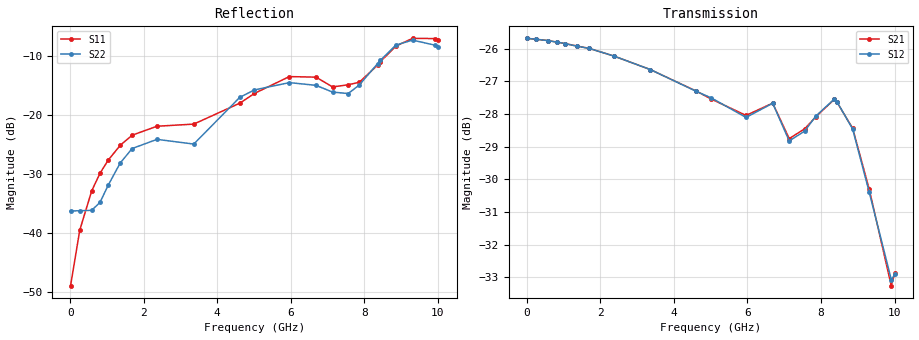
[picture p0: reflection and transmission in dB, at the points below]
! Device ID: PE43704
! Dir: z:\PE43704\PE43704_Char_1_20130516\PE43704\AMB\3p400V\24p75dB
! Serial: 14
! Insertion: A
! Impedance: 50 ohm
! Temp: Amb
! VDD: 3.400V
! Attenuation Step: 24.75dB
! IDD: 1.140146e-01mA
#  Hz  S  RI  R  50
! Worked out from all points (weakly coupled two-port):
!   401 points, 10 MHz to 10.01 GHz, reference 50 ohm
!   highest |S21| = -25.68 dB at 10 MHz (marker M1); lowest = -33.2 dB at 9.91 GHz (marker M2)
!   lowest |S11| = -48.9 dB at 10 MHz (marker M3), VSWR 1.01, Z = 50.4 + j0.0427 ohm
!   |S11| at or under -10 dB: start of sweep to 8.562 GHz
!   |S22| runs from -36.3 to -7.2 dB; largest |S21 - S12| = 0.0006
!   S11 on the Smith chart (normalised r, x): 10 MHz: 1.01, +0.00; 4.61 GHz: 0.79, +0.08; 8.435 GHz: 0.76, +0.46; 9.31 GHz: 0.51, +0.52; 10.01 GHz: 0.44, +0.31
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1e7  0.00358 0.000424  0.052 -9.25e-05  0.052 -6.29e-05  0.0155 0.000298
2.6e8  0.00114 0.0106  0.0517 -0.00359  0.0517 -0.00355  0.013 0.00852
5.85e8  -0.00966 0.0208  0.051 -0.00782  0.051 -0.00773  0.00244 0.0155
8.1e8  -0.0214 0.0242  0.0502 -0.0106  0.0502 -0.0107  -0.00851 0.0162
1.035e9  -0.0345 0.0236  0.0493 -0.0133  0.0493 -0.0133  -0.0217 0.0137
1.36e9  -0.053 0.0172  0.0476 -0.0172  0.0476 -0.0171  -0.0392 0.00454
1.685e9  -0.0676 0.00646  0.0457 -0.0208  0.0457 -0.0208  -0.0517 -0.0082
2.36e9  -0.0796 -0.0142  0.0406 -0.0272  0.0406 -0.0272  -0.0573 -0.0252
3.36e9  -0.0836 -0.0108  0.0315 -0.0343  0.0315 -0.0343  -0.057 -0.00322
4.61e9  -0.1165 0.0498  0.0201 -0.0382  0.02 -0.0382  -0.1279 0.0615
5.01e9  -0.1359 0.071  0.0172 -0.0383  0.0174 -0.0384  -0.1502 0.0663
5.96e9  -0.1866 0.1027  0.00975 -0.0384  0.0098 -0.0381  -0.1727 0.0778
6.685e9  -0.1873 0.0963  0.00556 -0.041  0.00539 -0.041  -0.1568 0.0873
7.135e9  -0.1548 0.0796  -0.000396 -0.0365  -0.000405 -0.0362  -0.1149 0.1076
7.56e9  -0.1297 0.127  -0.000491 -0.0378  -0.000403 -0.0375  -0.0731 0.1344
7.86e9  -0.094 0.1658  -0.00183 -0.0394  -0.00177 -0.0395  -0.0596 0.1704
8.36e9  -0.0595 0.2596  -0.0112 -0.0404  -0.011 -0.0405  -0.0662 0.2662
8.435e9  -0.0608 0.2788  -0.0127 -0.0395  -0.0123 -0.0397  -0.0732 0.2832
8.86e9  -0.1005 0.3729  -0.0189 -0.0328  -0.0187 -0.0328  -0.1202 0.3755
9.31e9  -0.1822 0.4102  -0.0181 -0.0246  -0.0181 -0.0242  -0.1944 0.3877
9.91e9  -0.311 0.3213  -0.00773 -0.0203  -0.00776 -0.0208  -0.302 0.2525
1.001e10  -0.3283 0.2887  -0.00617 -0.0219  -0.00602 -0.0218  -0.3129 0.2154
